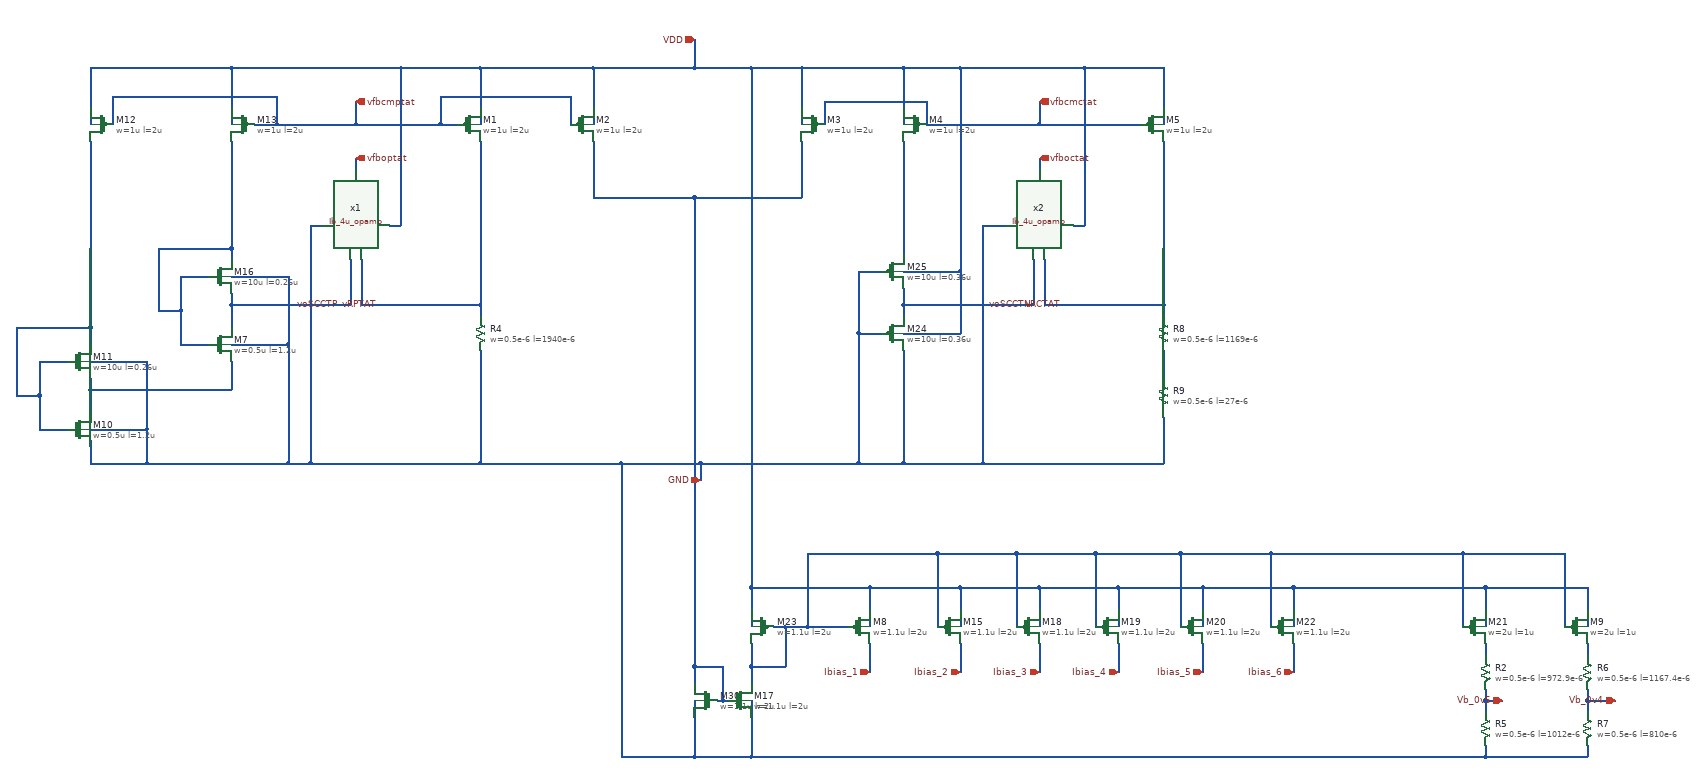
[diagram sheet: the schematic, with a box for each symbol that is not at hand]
v {xschem version=3.4.6 file_version=1.2}
G {}
K {}
V {}
S {}
E {}
N 1840 -1220 1840 -1180 {lab=vfbcmctat}
N 1720 -920 1760 -920 {lab=GND}
N 1720 -810 1760 -810 {lab=GND}
N 1800 -860 1800 -840 {lab=voSCCTN}
N 1250 -1280 1250 -1180 {lab=VDD}
N 1620 -1280 1620 -1180 {lab=VDD}
N 360 -1280 610 -1280 {lab=VDD}
N 1050 -1280 1050 -1180 {lab=VDD}
N 910 -1280 1050 -1280 {lab=VDD}
N 980 -1180 1010 -1180 {lab=vfbcmptat}
N 980 -1230 980 -1180 {lab=vfbcmptat}
N 1210 -1230 1210 -1180 {lab=vfbcmptat}
N 1660 -1220 1660 -1180 {lab=vfbcmctat}
N 610 -1280 610 -1180 {lab=VDD}
N 890 -1000 910 -1000 {lab=VDD}
N 910 -1280 910 -1000 {lab=VDD}
N 610 -1280 910 -1280 {lab=VDD}
N 610 -860 610 -820 {lab=voSCCTP}
N 610 -910 710 -910 {lab=GND}
N 710 -910 710 -790 {lab=GND}
N 610 -790 710 -790 {lab=GND}
N 520 -910 570 -910 {lab=#net1}
N 520 -850 520 -790 {lab=#net1}
N 520 -790 570 -790 {lab=#net1}
N 610 -960 610 -940 {lab=#net1}
N 480 -850 520 -850 {lab=#net1}
N 520 -910 520 -850 {lab=#net1}
N 480 -960 480 -850 {lab=#net1}
N 480 -960 610 -960 {lab=#net1}
N 610 -1150 610 -960 {lab=#net1}
N 610 -860 820 -860 {lab=voSCCTP}
N 610 -880 610 -860 {lab=voSCCTP}
N 820 -940 820 -860 {lab=voSCCTP}
N 360 -710 360 -670 {lab=#net2}
N 360 -760 460 -760 {lab=GND}
N 460 -760 460 -640 {lab=GND}
N 360 -640 460 -640 {lab=GND}
N 270 -760 320 -760 {lab=#net3}
N 270 -700 270 -640 {lab=#net3}
N 270 -640 320 -640 {lab=#net3}
N 230 -700 270 -700 {lab=#net3}
N 270 -760 270 -700 {lab=#net3}
N 360 -710 610 -710 {lab=#net2}
N 360 -730 360 -710 {lab=#net2}
N 610 -760 610 -710 {lab=#net2}
N 360 -820 360 -790 {lab=#net3}
N 400 -1230 690 -1230 {lab=vfbcmptat}
N 690 -1230 690 -1180 {lab=vfbcmptat}
N 650 -1180 690 -1180 {lab=vfbcmptat}
N 360 -620 360 -580 {lab=GND}
N 230 -820 230 -700 {lab=#net3}
N 230 -820 360 -820 {lab=#net3}
N 360 -1150 360 -820 {lab=#net3}
N 1720 -920 1720 -810 {lab=GND}
N 710 -790 710 -580 {lab=GND}
N 460 -580 710 -580 {lab=GND}
N 460 -640 460 -580 {lab=GND}
N 360 -580 460 -580 {lab=GND}
N 2120 -1280 2260 -1280 {lab=VDD}
N 1050 -860 1050 -840 {lab=vRPTAT}
N 1050 -780 1050 -580 {lab=GND}
N 840 -940 840 -860 {lab=vRPTAT}
N 1050 -1150 1050 -860 {lab=vRPTAT}
N 2260 -860 2260 -840 {lab=vRCTAT}
N 2260 -1150 2260 -860 {lab=vRCTAT}
N 1800 -1150 1800 -950 {lab=#net4}
N 1800 -780 1800 -580 {lab=GND}
N 1800 -890 1800 -860 {lab=voSCCTN}
N 1940 -1000 1980 -1000 {lab=GND}
N 1940 -1000 1940 -580 {lab=GND}
N 1800 -580 1940 -580 {lab=GND}
N 2100 -1000 2120 -1000 {lab=VDD}
N 2120 -1280 2120 -1000 {lab=VDD}
N 1900 -1280 2120 -1280 {lab=VDD}
N 1720 -580 1800 -580 {lab=GND}
N 1720 -810 1720 -580 {lab=GND}
N 1050 -1280 1250 -1280 {lab=VDD}
N 1800 -1280 1900 -1280 {lab=VDD}
N 1530 -1280 1620 -1280 {lab=VDD}
N 750 -1000 770 -1000 {lab=GND}
N 750 -1000 750 -580 {lab=GND}
N 1250 -1150 1250 -1050 {lab=#net5}
N 1620 -1150 1620 -1050 {lab=#net5}
N 1430 -1330 1430 -1280 {lab=VDD}
N 1250 -1280 1430 -1280 {lab=VDD}
N 1440 -580 1720 -580 {lab=GND}
N 1440 -580 1440 -550 {lab=GND}
N 1300 -580 1300 -60 {lab=GND}
N 1050 -580 1300 -580 {lab=GND}
N 1430 -160 1430 -60 {lab=GND}
N 1430 -220 1430 -190 {lab=#net5}
N 1480 -160 1490 -160 {lab=#net5}
N 1300 -60 1430 -60 {lab=GND}
N 1430 -1280 1530 -1280 {lab=VDD}
N 1430 -220 1480 -220 {lab=#net5}
N 1530 -220 1530 -190 {lab=#net6}
N 1430 -60 1530 -60 {lab=GND}
N 1530 -360 1530 -290 {lab=VDD}
N 1630 -290 1700 -290 {lab=#net6}
N 1900 -360 1900 -290 {lab=VDD}
N 2040 -360 2040 -290 {lab=VDD}
N 1900 -360 2040 -360 {lab=VDD}
N 1740 -260 1740 -210 {lab=Ibias_1}
N 2180 -360 2180 -290 {lab=VDD}
N 2040 -360 2180 -360 {lab=VDD}
N 2330 -360 2330 -290 {lab=VDD}
N 2180 -360 2330 -360 {lab=VDD}
N 2490 -360 2490 -290 {lab=VDD}
N 2330 -360 2490 -360 {lab=VDD}
N 1530 -160 1530 -60 {lab=GND}
N 1630 -420 1630 -290 {lab=#net6}
N 1590 -290 1630 -290 {lab=#net6}
N 2490 -260 2490 -210 {lab=Ibias_6}
N 2330 -260 2330 -210 {lab=Ibias_5}
N 2180 -260 2180 -210 {lab=Ibias_4}
N 2040 -260 2040 -210 {lab=Ibias_3}
N 1900 -260 1900 -210 {lab=Ibias_2}
N 1740 -360 1740 -290 {lab=VDD}
N 1530 -360 1740 -360 {lab=VDD}
N 2450 -420 2450 -290 {lab=#net6}
N 2290 -420 2450 -420 {lab=#net6}
N 2290 -420 2290 -290 {lab=#net6}
N 2140 -420 2290 -420 {lab=#net6}
N 2140 -420 2140 -290 {lab=#net6}
N 2000 -420 2140 -420 {lab=#net6}
N 2000 -420 2000 -290 {lab=#net6}
N 1860 -420 2000 -420 {lab=#net6}
N 1860 -420 1860 -290 {lab=#net6}
N 1530 -220 1590 -220 {lab=#net6}
N 1530 -260 1530 -220 {lab=#net6}
N 1590 -290 1590 -220 {lab=#net6}
N 1570 -290 1590 -290 {lab=#net6}
N 2830 -260 2830 -240 {lab=#net7}
N 2830 -80 2830 -60 {lab=GND}
N 2830 -160 2830 -140 {lab=Vb_0v5}
N 2830 -160 2860 -160 {lab=Vb_0v5}
N 2830 -180 2830 -160 {lab=Vb_0v5}
N 3010 -260 3010 -240 {lab=#net8}
N 3010 -160 3010 -140 {lab=Vb_0v4}
N 2830 -60 3010 -60 {lab=GND}
N 3010 -80 3010 -60 {lab=GND}
N 3010 -160 3060 -160 {lab=Vb_0v4}
N 3010 -180 3010 -160 {lab=Vb_0v4}
N 2450 -420 2790 -420 {lab=#net6}
N 2830 -360 3010 -360 {lab=VDD}
N 2490 -360 2830 -360 {lab=VDD}
N 1530 -60 2830 -60 {lab=GND}
N 3010 -360 3010 -290 {lab=VDD}
N 2790 -420 2790 -290 {lab=#net6}
N 2790 -420 2970 -420 {lab=#net6}
N 2970 -420 2970 -290 {lab=#net6}
N 2830 -360 2830 -290 {lab=VDD}
N 710 -580 750 -580 {lab=GND}
N 1630 -420 1860 -420 {lab=#net6}
N 1740 -360 1900 -360 {lab=VDD}
N 360 -1280 360 -1180 {lab=VDD}
N 400 -1230 400 -1180 {lab=vfbcmptat}
N 1480 -220 1480 -160 {lab=#net5}
N 1470 -160 1480 -160 {lab=#net5}
N 1430 -1050 1620 -1050 {lab=#net5}
N 1300 -580 1440 -580 {lab=GND}
N 1530 -1280 1530 -360 {lab=VDD}
N 980 -1230 1210 -1230 {lab=vfbcmptat}
N 1660 -1220 1840 -1220 {lab=vfbcmctat}
N 1430 -1050 1430 -220 {lab=#net5}
N 1250 -1050 1430 -1050 {lab=#net5}
N 2040 -1180 2220 -1180 {lab=vfbcmctat}
N 830 -1180 980 -1180 {lab=vfbcmptat}
N 2050 -940 2050 -860 {lab=vRCTAT}
N 2030 -940 2030 -860 {lab=voSCCTN}
N 1800 -1280 1800 -1180 {lab=VDD}
N 1620 -1280 1800 -1280 {lab=VDD}
N 2260 -1280 2260 -1180 {lab=VDD}
N 1800 -860 2030 -860 {lab=voSCCTN}
N 1800 -920 1900 -920 {lab=VDD}
N 1900 -1280 1900 -920 {lab=VDD}
N 1900 -920 1900 -810 {lab=VDD}
N 1800 -810 1900 -810 {lab=VDD}
N 830 -1120 830 -1100 {lab=vfboptat}
N 830 -1220 830 -1180 {lab=vfbcmptat}
N 690 -1180 830 -1180 {lab=vfbcmptat}
N 2040 -1220 2040 -1180 {lab=vfbcmctat}
N 1840 -1180 2040 -1180 {lab=vfbcmctat}
N 2040 -1120 2040 -1100 {lab=vfboctat}
N 2050 -860 2260 -860 {lab=vRCTAT}
N 1940 -580 2260 -580 {lab=GND}
N 840 -860 1050 -860 {lab=vRPTAT}
N 750 -580 1050 -580 {lab=GND}
N 2260 -780 2260 -730 {lab=#net9}
N 2260 -660 2260 -580 {lab=GND}
C {iopin.sym} 1430 -1330 0 0 {name=p1 lab=VDD}
C {iopin.sym} 1440 -550 0 0 {name=p2 lab=GND}
C {iopin.sym} 1740 -210 0 0 {name=p3 lab=Ibias_1}
C {lab_pin.sym} 800 -860 3 0 {name=p9 sig_type=std_logic lab=voSCCTP}
C {lab_pin.sym} 2030 -860 3 0 {name=p10 sig_type=std_logic lab=voSCCTN}
C {lab_pin.sym} 2080 -860 3 0 {name=p11 sig_type=std_logic lab=vRCTAT}
C {lab_pin.sym} 870 -860 3 0 {name=p12 sig_type=std_logic lab=vRPTAT}
C {sg13g2_pr/sg13_lv_pmos.sym} 1030 -1180 0 0 {name=M1
l=2u
w=1u
ng=1
m=1
model=sg13_lv_pmos
spiceprefix=X
}
C {sg13g2_pr/sg13_lv_pmos.sym} 1230 -1180 0 0 {name=M2
l=2u
w=1u
ng=1
m=6
model=sg13_lv_pmos
spiceprefix=X
}
C {sg13g2_pr/sg13_lv_pmos.sym} 1640 -1180 0 1 {name=M3
l=2u
w=1u
ng=1
m=6
model=sg13_lv_pmos
spiceprefix=X
}
C {sg13g2_pr/sg13_lv_pmos.sym} 1820 -1180 0 1 {name=M4
l=2u
w=1u
ng=1
m=1
model=sg13_lv_pmos
spiceprefix=X
}
C {sg13g2_pr/sg13_lv_pmos.sym} 380 -1180 0 1 {name=M12
l=2u
w=1u
ng=1
m=1
model=sg13_lv_pmos
spiceprefix=X
}
C {sg13g2_pr/sg13_lv_pmos.sym} 630 -1180 0 1 {name=M13
l=2u
w=1u
ng=1
m=1
model=sg13_lv_pmos
spiceprefix=X
}
C {sg13g2_pr/sg13_lv_pmos.sym} 2240 -1180 0 0 {name=M5
l=2u
w=1u
ng=1
m=1
model=sg13_lv_pmos
spiceprefix=X
}
C {sg13g2_pr/sg13_lv_nmos.sym} 590 -790 0 0 {name=M7
l=1.2u
w=0.5u
ng=1
m=1
model=sg13_lv_nmos
spiceprefix=X
}
C {sg13g2_pr/sg13_lv_nmos.sym} 340 -640 0 0 {name=M10
l=1.2u
w=0.5u
ng=1
m=1
model=sg13_lv_nmos
spiceprefix=X
}
C {sg13g2_pr/sg13_lv_nmos.sym} 340 -760 0 0 {name=M11
l=0.26u
w=10u
ng=1
m=20
model=sg13_lv_nmos
spiceprefix=X
}
C {sg13g2_pr/sg13_lv_nmos.sym} 590 -910 0 0 {name=M16
l=0.26u
w=10u
ng=1
m=20
model=sg13_lv_nmos
spiceprefix=X
}
C {iopin.sym} 1900 -210 0 0 {name=p4 lab=Ibias_2}
C {iopin.sym} 2040 -210 0 0 {name=p5 lab=Ibias_3}
C {iopin.sym} 2180 -210 0 0 {name=p6 lab=Ibias_4}
C {iopin.sym} 2330 -210 0 0 {name=p7 lab=Ibias_5}
C {iopin.sym} 2490 -210 0 0 {name=p8 lab=Ibias_6}
C {/shared/designs/SSDOR_w_startup_1V_ihp/Ib_4u/Ib_4u_opamp/Ib_4u_opamp.sym} 770 -940 1 1 {name=x1}
C {/shared/designs/SSDOR_w_startup_1V_ihp/Ib_4u/Ib_4u_opamp/Ib_4u_opamp.sym} 1980 -940 1 1 {name=x2}
C {sg13g2_pr/sg13_lv_nmos.sym} 1450 -160 0 1 {name=M30
l=2u
w=1.1u
ng=1
m=3
model=sg13_lv_nmos
spiceprefix=X
}
C {sg13g2_pr/rppd.sym} 2830 -210 0 0 {name=R2
w=0.5e-6
l=972.9e-6
model=rppd
body=GND
spiceprefix=X
b=0
m=1
}
C {sg13g2_pr/rppd.sym} 3010 -210 0 0 {name=R6
w=0.5e-6
l=1167.4e-6
model=rppd
body=GND
spiceprefix=X
b=0
m=1
}
C {sg13g2_pr/rppd.sym} 3010 -110 0 0 {name=R7
w=0.5e-6
l=810e-6
model=rppd
body=GND
spiceprefix=X
b=0
m=1
}
C {iopin.sym} 3060 -160 0 0 {name=p16 lab=Vb_0v4}
C {iopin.sym} 2860 -160 0 0 {name=p17 lab=Vb_0v5}
C {sg13g2_pr/rppd.sym} 2830 -110 0 0 {name=R5
w=0.5e-6
l=1012e-6
model=rppd
body=GND
spiceprefix=X
b=0
m=1
}
C {sg13g2_pr/sg13_lv_nmos.sym} 1510 -160 0 0 {name=M17
l=2u
w=1.1u
ng=1
m=3
model=sg13_lv_nmos
spiceprefix=X
}
C {sg13g2_pr/sg13_lv_pmos.sym} 2810 -290 0 0 {name=M21
l=1u
w=2u
ng=1
m=1
model=sg13_lv_pmos
spiceprefix=X
}
C {sg13g2_pr/sg13_lv_pmos.sym} 2990 -290 0 0 {name=M9
l=1u
w=2u
ng=1
m=1
model=sg13_lv_pmos
spiceprefix=X
}
C {sg13g2_pr/sg13_lv_pmos.sym} 1550 -290 0 1 {name=M23
l=2u
w=1.1u
ng=1
m=6
model=sg13_lv_pmos
spiceprefix=X
}
C {sg13g2_pr/rppd.sym} 1050 -810 0 0 {name=R4
w=0.5e-6
l=1940e-6
model=rppd
body=GND
spiceprefix=X
b=0
m=1
}
C {sg13g2_pr/rppd.sym} 2260 -810 0 0 {name=R8
w=0.5e-6
l=1169e-6
model=rppd
body=GND
spiceprefix=X
b=0
m=1
}
C {sg13g2_pr/rhigh.sym} 2260 -700 0 0 {name=R9
w=0.5e-6
l=27e-6
model=rhigh
body=GND
spiceprefix=X
b=0
m=1
}
C {sg13g2_pr/sg13_lv_pmos.sym} 1720 -290 0 0 {name=M8
l=2u
w=1.1u
ng=1
m=6
model=sg13_lv_pmos
spiceprefix=X
}
C {sg13g2_pr/sg13_lv_pmos.sym} 1880 -290 0 0 {name=M15
l=2u
w=1.1u
ng=1
m=6
model=sg13_lv_pmos
spiceprefix=X
}
C {sg13g2_pr/sg13_lv_pmos.sym} 2020 -290 0 0 {name=M18
l=2u
w=1.1u
ng=1
m=6
model=sg13_lv_pmos
spiceprefix=X
}
C {sg13g2_pr/sg13_lv_pmos.sym} 2160 -290 0 0 {name=M19
l=2u
w=1.1u
ng=1
m=6
model=sg13_lv_pmos
spiceprefix=X
}
C {sg13g2_pr/sg13_lv_pmos.sym} 2310 -290 0 0 {name=M20
l=2u
w=1.1u
ng=1
m=6
model=sg13_lv_pmos
spiceprefix=X
}
C {sg13g2_pr/sg13_lv_pmos.sym} 2470 -290 0 0 {name=M22
l=2u
w=1.1u
ng=1
m=6
model=sg13_lv_pmos
spiceprefix=X
}
C {sg13g2_pr/sg13_lv_pmos.sym} 1780 -810 0 0 {name=M24
l=0.36u
w=10u
ng=1
m=60
model=sg13_lv_pmos
spiceprefix=X
}
C {sg13g2_pr/sg13_lv_pmos.sym} 1780 -920 0 0 {name=M25
l=0.36u
w=10u
ng=1
m=1
model=sg13_lv_pmos
spiceprefix=X
}
C {iopin.sym} 830 -1120 0 1 {name=p13 lab=vfboptat}
C {iopin.sym} 830 -1220 0 1 {name=p14 lab=vfbcmptat}
C {iopin.sym} 2040 -1220 0 1 {name=p15 lab=vfbcmctat}
C {iopin.sym} 2040 -1120 0 1 {name=p18 lab=vfboctat}
